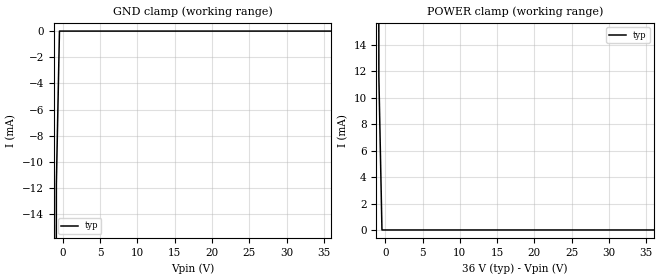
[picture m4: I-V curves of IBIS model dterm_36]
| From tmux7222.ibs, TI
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| dterm_36
[Model]   dterm_36
Model_type   Terminator
|   typ   min   max
C_comp   1.598234e-11   NA   NA
[Voltage Range]   36   NA   NA
[Temperature Range]   27   NA   NA
[Power Clamp Reference]   36   NA   NA
[GND Clamp Reference]   0   NA   NA
[GND Clamp]
|   Voltage   I(typ)   I(min)   I(max)
-5V       -4.875A    NA         NA
-1.273V   -264.2mA   NA         NA
-858.6mV  -11.69mA   NA         NA
-444.4mV  -16.03nA   NA         NA
36V       1.245nA    NA         NA
[POWER Clamp]
|   Voltage   I(typ)   I(min)   I(max)
-5V       5.382A     NA         NA
-1.273V   260.7mA    NA         NA
-858.6mV  11.57mA    NA         NA
-444.4mV  12.2nA     NA         NA
36V       -1.245nA   NA         NA
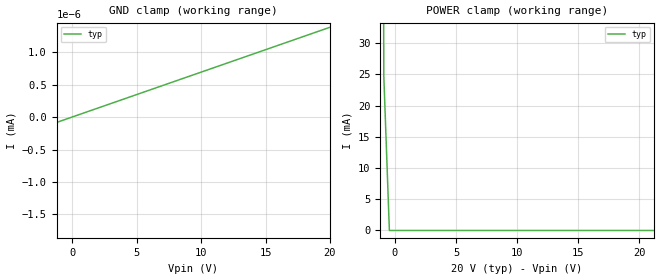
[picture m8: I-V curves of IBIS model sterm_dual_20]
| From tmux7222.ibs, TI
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| sterm_dual_20
[Model]   sterm_dual_20
Model_type   Terminator
|   typ   min   max
C_comp   1.598234e-11   NA   NA
[Voltage Range]   20   NA   NA
[Temperature Range]   27   NA   NA
[Power Clamp Reference]   20   NA   NA
[GND Clamp Reference]   0   NA   NA
[GND Clamp]
|   Voltage   I(typ)   I(min)   I(max)
-25V      -4.039A    NA         NA
-20.45V   -21.91nA   NA         NA
-20V      -1.383nA   NA         NA
20V       1.383nA    NA         NA
[POWER Clamp]
|   Voltage   I(typ)   I(min)   I(max)
-5V       4.767A     NA         NA
-1.364V   320.6mA    NA         NA
-909.1mV  24.61mA    NA         NA
-454.5mV  16.97nA    NA         NA
40V       -1.383nA   NA         NA
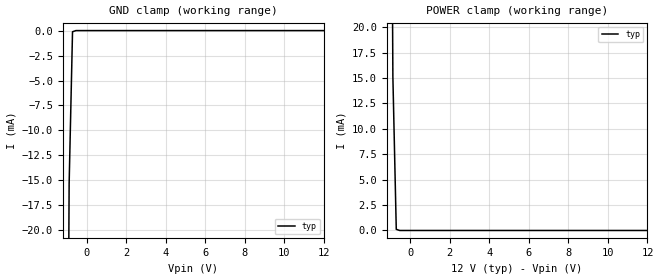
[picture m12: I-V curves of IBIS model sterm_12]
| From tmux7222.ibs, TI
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| sterm_12
[Model]   sterm_12
Model_type   Terminator
|   typ   min   max
C_comp   1.008417e-11   NA   NA
[Voltage Range]   12   NA   NA
[Temperature Range]   27   NA   NA
[Power Clamp Reference]   12   NA   NA
[GND Clamp Reference]   0   NA   NA
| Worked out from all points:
|   GND clamp passes 1 mA (typ) near -0.72 V on its own axis
|   POWER clamp passes 1 mA (typ) near -0.72 V on its own axis
[GND Clamp]
|   Voltage   I(typ)   I(min)   I(max)
-5V       -3.868A    NA         NA
-1.051V   -77.67mA   NA         NA
-878.8mV  -15.4mA    NA         NA
-707.1mV  -116.4uA   NA         NA
-535.4mV  -304.8nA   NA         NA
12V       416pA      NA         NA
[POWER Clamp]
|   Voltage   I(typ)   I(min)   I(max)
-5V       4.761A     NA         NA
-1.05V    76.19mA    NA         NA
-878.8mV  15.12mA    NA         NA
-707.1mV  114.5uA    NA         NA
-535.4mV  269nA      NA         NA
12V       -416.3pA   NA         NA
